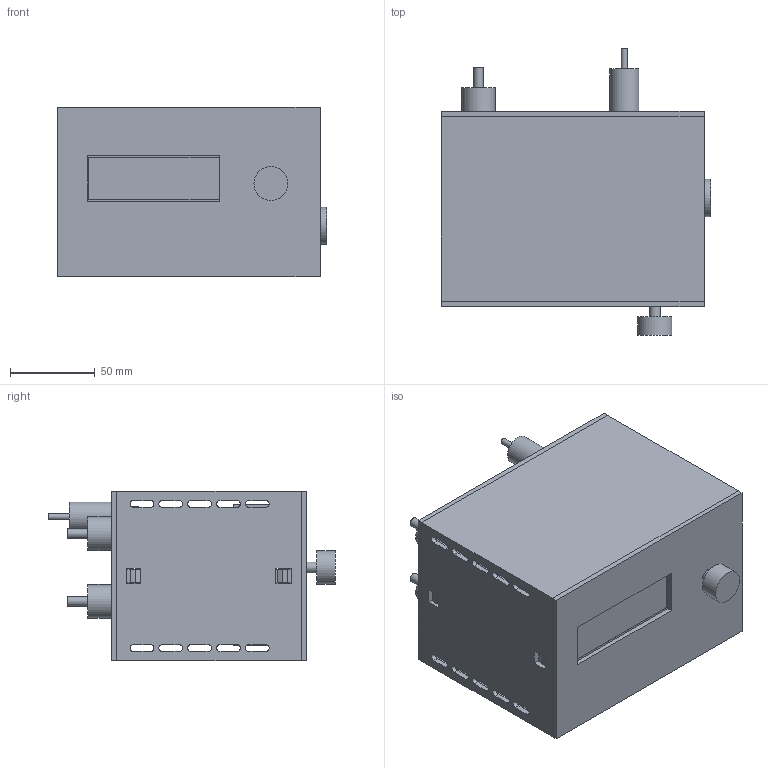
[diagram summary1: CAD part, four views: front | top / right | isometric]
STEP (ISO 10303-21) file: header records copied from the file, then geometry measured from it (millimetres).
FILE_DESCRIPTION(('Open CASCADE Model'),'2;1');
FILE_NAME('Open CASCADE Shape Model','2026-11-05T16:43:00',('Author'),( 'Open CASCADE'),'Open CASCADE STEP processor 7.8','Open CASCADE 7.8' ,'Unknown');
FILE_SCHEMA(('AUTOMOTIVE_DESIGN { 1 0 10303 214 1 1 1 1 }'));
Length unit declared in the file: millimetre
Products named in the file (106): Laboratory_controller_fit_study_07_integrated_buck; 01_Pieces_imprimees; 01_Shell_open_front_and_rear; 02_Removable_front_LCD_A; 03_B_removable_carrier; 04_Rear_panel_with_latches; 02_Carte_A_reference; PCB_A; A_C1_ENVELOPE; A_C2_ENVELOPE; A_C3_ENVELOPE; A_D1_ENVELOPE; A_D2_ENVELOPE; A_J1_ENVELOPE; A_J2_ENVELOPE; A_J3_ENVELOPE; A_J4_ENVELOPE; A_J5_ENVELOPE; A_J6_ENVELOPE; A_J7_ENVELOPE; A_JP1_ENVELOPE; A_R1_ENVELOPE; A_R2_ENVELOPE; A_R3_ENVELOPE; A_R4_ENVELOPE; A_R5_ENVELOPE; A_R6_ENVELOPE; A_R7_ENVELOPE; A_U2_ENVELOPE; A_DEVKIT_SOCKET_34.03; A_DEVKIT_SOCKET_59.43; A_DIYMORE_PCB_54x27; A_DIYMORE_RF_SHIELD; A_DIYMORE_CH340; A_DIYMORE_USB_C; 03_Carte_B_reference; PCB_B; B_R3_ENVELOPE; B_C3_ENVELOPE; B_L1_ENVELOPE ...
Assembly tree (105 placements, depth 3):
  Laboratory_controller_fit_study_07_integrated_buck
    01_Pieces_imprimees
      01_Shell_open_front_and_rear
      02_Removable_front_LCD_A
      03_B_removable_carrier
      04_Rear_panel_with_latches
    02_Carte_A_reference
      PCB_A
      A_C1_ENVELOPE
      A_C2_ENVELOPE
      A_C3_ENVELOPE
      A_D1_ENVELOPE
      A_D2_ENVELOPE
      A_J1_ENVELOPE
      A_J2_ENVELOPE
      A_J3_ENVELOPE
      A_J4_ENVELOPE
      A_J5_ENVELOPE
      A_J6_ENVELOPE
      A_J7_ENVELOPE
      A_JP1_ENVELOPE
      A_R1_ENVELOPE
      A_R2_ENVELOPE
      A_R3_ENVELOPE
      A_R4_ENVELOPE
      A_R5_ENVELOPE
      A_R6_ENVELOPE
      A_R7_ENVELOPE
      A_U2_ENVELOPE
      A_DEVKIT_SOCKET_34.03
      A_DEVKIT_SOCKET_59.43
      A_DIYMORE_PCB_54x27
      A_DIYMORE_RF_SHIELD
      A_DIYMORE_CH340
      A_DIYMORE_USB_C
    03_Carte_B_reference
      PCB_B
      B_R3_ENVELOPE
      B_C3_ENVELOPE
      B_L1_ENVELOPE
      B_J4_ENVELOPE
      B_D9_ENVELOPE
      B_R12_ENVELOPE
      B_U5_ENVELOPE
      B_C5_ENVELOPE
      B_R5_ENVELOPE
      B_R11_ENVELOPE
      B_C2_ENVELOPE
      B_C8_ENVELOPE
      B_D4_ENVELOPE
      B_C6_ENVELOPE
      B_R13_ENVELOPE
      B_Q2_ENVELOPE
      B_F1_ENVELOPE
      B_C4_ENVELOPE
      B_D3_ENVELOPE
      B_J3_ENVELOPE
      B_R4_ENVELOPE
      B_Q1_ENVELOPE
      B_C7_ENVELOPE
Bounding box: 159 x 169 x 100 mm (x, y, z)
Volume: 420056.3 mm3; surface area: 316580.7 mm2
Topology: 99 solids, 99 shells, 1046 faces, 2450 edges, 1621 vertices
Faces by surface type: plane 961, cylinder 85
Full cylindrical faces by diameter (mm): 2.2 x12, 3 x3, 3.5 x1, 4.3 x1, 5.5 x2, 6.3 x2, 6.4 x1, 7.2 x1, 8 x1, 12 x6, 12.4 x1, 12.5 x2, 15 x2, 16 x1, 17 x2, 20 x5, 22 x2
Entity records: 63247 total; most frequent: CARTESIAN_POINT 11365, DIRECTION 8876, LINE 6007, VECTOR 6007, ORIENTED_EDGE 4900, PCURVE 4900, DEFINITIONAL_REPRESENTATION 4900, EDGE_CURVE 2450
